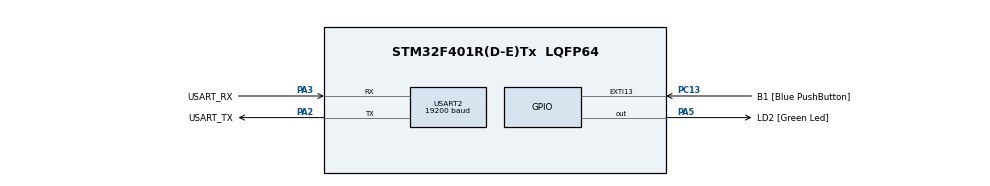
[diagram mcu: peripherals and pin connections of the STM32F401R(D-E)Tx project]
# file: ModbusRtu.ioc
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Mcu.Family=STM32F4
Mcu.Name=STM32F401R(D-E)Tx
Mcu.Package=LQFP64
NVIC.PriorityGroup=NVIC_PRIORITYGROUP_0
NVIC.USART2_IRQn=true\:0\:0\:false\:false\:true\:true\:true\:true
PA13.GPIO_Label=TMS
PA13.Mode=Serial_Wire
PA13.Signal=SYS_JTMS-SWDIO
PA14.GPIO_Label=TCK
PA14.Mode=Serial_Wire
PA14.Signal=SYS_JTCK-SWCLK
PA2.GPIO_Label=USART_TX
PA2.GPIO_Mode=GPIO_MODE_AF_PP
PA2.GPIO_PuPd=GPIO_NOPULL
PA2.GPIO_Speed=GPIO_SPEED_FREQ_LOW
PA2.Mode=Asynchronous
PA2.Signal=USART2_TX
PA3.GPIO_Label=USART_RX
PA3.GPIO_Mode=GPIO_MODE_AF_PP
PA3.GPIO_PuPd=GPIO_NOPULL
PA3.GPIO_Speed=GPIO_SPEED_FREQ_LOW
PA3.Mode=Asynchronous
PA3.Signal=USART2_RX
PA5.GPIO_Label=LD2 [Green Led]
PA5.GPIO_Mode=GPIO_MODE_OUTPUT_PP
PA5.GPIO_PuPd=GPIO_NOPULL
PA5.GPIO_Speed=GPIO_SPEED_FREQ_LOW
PA5.Signal=GPIO_Output
PB3.GPIO_Label=SWO
PB3.Signal=SYS_JTDO-SWO
PC13-ANTI_TAMP.GPIO_Label=B1 [Blue PushButton]
PC13-ANTI_TAMP.GPIO_ModeDefaultEXTI=GPIO_MODE_IT_FALLING
PC13-ANTI_TAMP.GPIO_PuPd=GPIO_NOPULL
PC13-ANTI_TAMP.Signal=GPXTI13
PC14-OSC32_IN.Mode=LSE-External-Oscillator
PC14-OSC32_IN.Signal=RCC_OSC32_IN
PC15-OSC32_OUT.Mode=LSE-External-Oscillator
PC15-OSC32_OUT.Signal=RCC_OSC32_OUT
PH0\ -\ OSC_IN.Mode=HSE-External-Clock-Source
PH0\ -\ OSC_IN.Signal=RCC_OSC_IN
PH1\ -\ OSC_OUT.Mode=HSE-External-Clock-Source
PH1\ -\ OSC_OUT.Signal=RCC_OSC_OUT
ProjectManager.HeapSize=0x200
ProjectManager.StackSize=0x400
ProjectManager.TargetToolchain=STM32CubeIDE
RCC.48MHZClocksFreq_Value=24000000
RCC.AHBFreq_Value=84000000
RCC.APB1CLKDivider=RCC_HCLK_DIV2
RCC.APB1Freq_Value=42000000
RCC.APB1TimFreq_Value=84000000
RCC.APB2Freq_Value=84000000
RCC.APB2TimFreq_Value=84000000
RCC.CortexFreq_Value=84000000
RCC.HCLKFreq_Value=84000000
RCC.HSE_VALUE=8000000
RCC.HSI_VALUE=16000000
RCC.PLLM=4
RCC.PLLN=84
RCC.PLLQ=7
RCC.PLLSourceVirtual=RCC_PLLSOURCE_HSE
RCC.SYSCLKFreq_VALUE=84000000
RCC.SYSCLKSource=RCC_SYSCLKSOURCE_PLLCLK
RCC.VCOOutputFreq_Value=168000000
TIM10.Prescaler=4199
USART2.BaudRate=19200
USART2.Parity=PARITY_EVEN
USART2.VirtualMode=VM_ASYNC
USART2.WordLength=WORDLENGTH_9B
VP_TIM10_VS_ClockSourceINT.Mode=Enable_Timer
board=NUCLEO-F401RE

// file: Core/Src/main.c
/* USER CODE BEGIN Header */
/**
  ******************************************************************************
  * @file           : main.c
  * @brief          : Main program body
  ******************************************************************************
  * @attention
  *
  * Copyright (c) 2023 STMicroelectronics.
  * All rights reserved.
  *
  * This software is licensed under terms that can be found in the LICENSE file
  * in the root directory of this software component.
  * If no LICENSE file comes with this software, it is provided AS-IS.
  *
  ******************************************************************************
  */
/* USER CODE END Header */
#include "main.h"
#include "microtbx.h"
#include "microtbxmodbus.h"

TIM_HandleTypeDef htim10;

UART_HandleTypeDef huart2;

/* USER CODE BEGIN PV */
tTbxMbTp modbusTp;
tTbxMbServer modbusServer;
/* USER CODE END PV */

void SystemClock_Config(void);
static void MX_GPIO_Init(void);
static void MX_USART2_UART_Init(void);
static void MX_TIM10_Init(void);

/* USER CODE BEGIN 0 */
tTbxMbServerResult ModbusReadInputReg(tTbxMbServer   channel,
                                      uint16_t       addr,
                                      uint16_t     * value)
{
  tTbxMbServerResult result = TBX_MB_SERVER_OK;

  /* Filter on the requested input register address. */
  switch (addr)
  {
  case 30000U:
    *value = 1234U;
    break;

  case 30001U:
    *value = 5678U;
    break;

  default:
    /* Unsupported input register address. */
    result = TBX_MB_SERVER_ERR_ILLEGAL_DATA_ADDR;
    break;
  }

  /* Give the result back to the caller. */
  return result;
}
/* USER CODE END 0 */

int main(void)
{

  /* MCU Configuration--------------------------------------------------------*/

  /* Reset of all peripherals, Initializes the Flash interface and the Systick. */
  HAL_Init();

  /* Configure the system clock */
  SystemClock_Config();

  /* Initialize all configured peripherals */
  MX_GPIO_Init();
  MX_USART2_UART_Init();
  MX_TIM10_Init();
  /* USER CODE BEGIN 2 */
  modbusTp = TbxMbRtuCreate(10, TBX_MB_UART_PORT1, TBX_MB_UART_19200BPS,
                            TBX_MB_UART_1_STOPBITS, TBX_MB_EVEN_PARITY);
  modbusServer = TbxMbServerCreate(modbusTp);
  TbxMbServerSetCallbackReadInputReg(modbusServer, ModbusReadInputReg);
  /* USER CODE END 2 */

  /* Infinite loop */
  while (1)
  {
    TbxMbEventTask();
  }
}

void SystemClock_Config(void)
{
  RCC_OscInitTypeDef RCC_OscInitStruct = {0};
  RCC_ClkInitTypeDef RCC_ClkInitStruct = {0};

  /** Configure the main internal regulator output voltage
  */
  __HAL_RCC_PWR_CLK_ENABLE();
  __HAL_PWR_VOLTAGESCALING_CONFIG(PWR_REGULATOR_VOLTAGE_SCALE2);

  /** Initializes the RCC Oscillators according to the specified parameters
  * in the RCC_OscInitTypeDef structure.
  */
  /*RCC_OscInitStruct.OscillatorType = RCC_OSCILLATORTYPE_HSE;
  RCC_OscInitStruct.HSEState = RCC_HSE_BYPASS;
  RCC_OscInitStruct.PLL.PLLState = RCC_PLL_ON;
  RCC_OscInitStruct.PLL.PLLSource = RCC_PLLSOURCE_HSE;
  RCC_OscInitStruct.PLL.PLLM = 4;
  RCC_OscInitStruct.PLL.PLLN = 84;
  RCC_OscInitStruct.PLL.PLLP = RCC_PLLP_DIV2;
  RCC_OscInitStruct.PLL.PLLQ = 7;
  if (HAL_RCC_OscConfig(&RCC_OscInitStruct) != HAL_OK)
  {
    Error_Handler();
  }*/

  /** Initializes the CPU, AHB and APB buses clocks
  */
  RCC_ClkInitStruct.ClockType = RCC_CLOCKTYPE_HCLK|RCC_CLOCKTYPE_SYSCLK
                              |RCC_CLOCKTYPE_PCLK1|RCC_CLOCKTYPE_PCLK2;
  RCC_ClkInitStruct.SYSCLKSource = RCC_SYSCLKSOURCE_HSI;
  RCC_ClkInitStruct.AHBCLKDivider = RCC_SYSCLK_DIV1;
  RCC_ClkInitStruct.APB1CLKDivider = RCC_HCLK_DIV2;
  RCC_ClkInitStruct.APB2CLKDivider = RCC_HCLK_DIV1;

  if (HAL_RCC_ClockConfig(&RCC_ClkInitStruct, FLASH_LATENCY_2) != HAL_OK)
  {
    Error_Handler();
  }
}

static void MX_TIM10_Init(void)
{

  htim10.Instance = TIM10;
  htim10.Init.Prescaler = 4199;
  htim10.Init.CounterMode = TIM_COUNTERMODE_UP;
  htim10.Init.Period = 65535;
  htim10.Init.ClockDivision = TIM_CLOCKDIVISION_DIV1;
  htim10.Init.AutoReloadPreload = TIM_AUTORELOAD_PRELOAD_DISABLE;
  if (HAL_TIM_Base_Init(&htim10) != HAL_OK)
  {
    Error_Handler();
  }

}

static void MX_USART2_UART_Init(void)
{

  huart2.Instance = USART1;
  huart2.Init.BaudRate = 19200;
  huart2.Init.WordLength = UART_WORDLENGTH_9B;
  huart2.Init.StopBits = UART_STOPBITS_1;
  huart2.Init.Parity = UART_PARITY_EVEN;
  huart2.Init.Mode = UART_MODE_TX_RX;
  huart2.Init.HwFlowCtl = UART_HWCONTROL_NONE;
  huart2.Init.OverSampling = UART_OVERSAMPLING_16;
  if (HAL_UART_Init(&huart2) != HAL_OK)
  {
    Error_Handler();
  }

}

static void MX_GPIO_Init(void)
{
  GPIO_InitTypeDef GPIO_InitStruct = {0};

  /* GPIO Ports Clock Enable */
  __HAL_RCC_GPIOC_CLK_ENABLE();
  __HAL_RCC_GPIOH_CLK_ENABLE();
  __HAL_RCC_GPIOA_CLK_ENABLE();
  __HAL_RCC_GPIOB_CLK_ENABLE();

  /*Configure GPIO pin Output Level */
  HAL_GPIO_WritePin(LD2_GPIO_Port, LD2_Pin, GPIO_PIN_RESET);

  /*Configure GPIO pin : B1_Pin */
  GPIO_InitStruct.Pin = B1_Pin;
  GPIO_InitStruct.Mode = GPIO_MODE_IT_FALLING;
  GPIO_InitStruct.Pull = GPIO_NOPULL;
  HAL_GPIO_Init(B1_GPIO_Port, &GPIO_InitStruct);

  /*Configure GPIO pin : LD2_Pin */
  GPIO_InitStruct.Pin = LD2_Pin;
  GPIO_InitStruct.Mode = GPIO_MODE_OUTPUT_PP;
  GPIO_InitStruct.Pull = GPIO_NOPULL;
  GPIO_InitStruct.Speed = GPIO_SPEED_FREQ_LOW;
  HAL_GPIO_Init(LD2_GPIO_Port, &GPIO_InitStruct);

}

void Error_Handler(void)
{
  __disable_irq();
  while (1)
  {
  }
}
